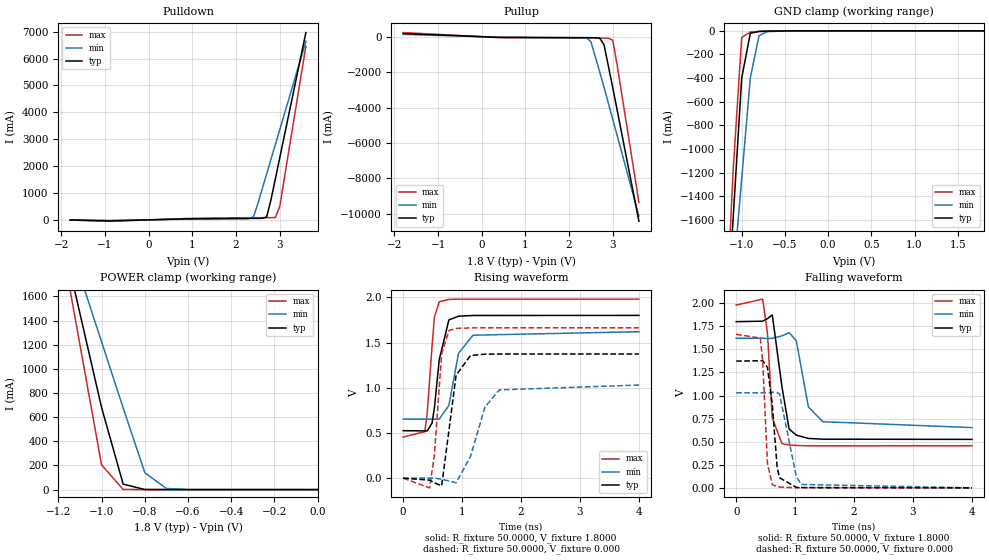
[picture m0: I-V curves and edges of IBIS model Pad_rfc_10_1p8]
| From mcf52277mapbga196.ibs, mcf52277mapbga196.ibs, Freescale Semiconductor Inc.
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|   Model Pad_rfc_10_1p8
[Model]   Pad_rfc_10_1p8
Model_type   3-state
Polarity   Non-Inverting
Enable   Active-High
Vmeas =   0.9000V
C_comp   1.7450pF   1.6200pF   1.8900pF
[Temperature Range]   25.0000   0.1500k   -40.0000
[Voltage Range]   1.8000V   1.6200V   1.9800V
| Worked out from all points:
|   slope of the pulldown table from 0 to 0.27 V, typ, clamps not added: 19 ohm
|   slope of the pullup table from 0 to 0.27 V, typ, clamps not added: 13.8 ohm
|   GND clamp passes 1 mA (typ) near -0.62 V on its own axis
|   POWER clamp passes 1 mA (typ) near -0.80 V on its own axis
|   rising waveform, R_fixture 50.0000, V_fixture 1.8000: 20-80 % time 147ps typ, 186ps min, 105ps max; typ from 0.525 V to 1.8 V
|   rising waveform, R_fixture 50.0000, V_fixture 0.000: 20-80 % time 158ps typ, 298ps min, 109ps max; typ from 0 V to 1.37 V
|   falling waveform, R_fixture 50.0000, V_fixture 1.8000: 20-80 % time 127ps typ, 192ps min, 81.5ps max; typ from 1.8 V to 0.525 V
|   falling waveform, R_fixture 50.0000, V_fixture 0.000: 20-80 % time 108ps typ, 167ps min, 72.6ps max; typ from 1.37 V to 0 V
[Pulldown]
| voltage   I(typ)   I(min)   I(max)
-1.8V     -4.24mA    -2.09mA    -7.86mA
-900mV    -41mA      -20.4mA    -54.37mA
900mV     38.52mA    24.29mA    52.61mA
2.3V      56.35mA    39.44mA    79.95mA
2.4V      56.6mA     115.4mA    80.28mA
2.5V      56.84mA    601.5mA    80.58mA
2.6V      57.95mA    1.15A      80.85mA
2.7V      102.6mA    1.699A     81.1mA
2.8V      738.4mA    2.247A     81.35mA
2.9V      1.517A     2.796A     85.38mA
3V        2.296A     3.345A     485.9mA
3.6V      6.968A     6.645A     6.46A
[Pullup]
| voltage   I(typ)   I(min)   I(max)
-1.8V     193.5mA    144.4mA    246.3mA
400mV     -26.32mA   -16.73mA   -39.42mA
2.4V      -41.73mA   -53.46mA   -62.76mA
2.5V      -43.5mA    -274.4mA   -63.07mA
2.7V      -61.67mA   -1.963A    -66.64mA
2.8V      -440.4mA   -2.842A    -70.12mA
2.9V      -1.643A    -3.748A    -75.32mA
3V        -2.874A    -4.656A    -184.4mA
3.1V      -4.121A    -5.562A    -1.567A
3.6V      -10.43A    -10.13A    -9.366A
[GND_clamp]
| voltage   I(typ)   I(min)   I(max)
-1.8V     -10.39A    -8.454A    -12.14A
-1.2V     -2.833A    -2.997A    -2.746A
-1.1V     -1.601A    -2.108A    -1.195A
-1V       -399mA     -1.252A    -56.61mA
-900mV    -20.31mA   -398.2mA   -10.19mA
-800mV    -5.193mA   -41.09mA   -5.939mA
-700mV    -2.389mA   -6.145mA   -2.797mA
-400mV    -10.19uA   -60.07uA   -3.537uA
1.8V      460.9pA    80.51nA    11.42pA
[POWER_clamp]
| voltage   I(typ)   I(min)   I(max)
-1.8V     6.91A      5.617A     8.169A
-1.2V     2.238A     2.322A     2.196A
-1.1V     1.459A     1.774A     1.2A
-1V       681mA      1.225A     205.3mA
-900mV    45.38mA    676.7mA    1.42mA
-800mV    926.3uA    140.3mA    9.915uA
-700mV    19.1uA     9.035mA    78.66nA
-600mV    427.3nA    583uA      682.7pA
0V        460.9pA    46.95nA    15.9pA
[Ramp]
| variable   typ   min   max
dV/dt_r   0.8238/0.1616n   0.6183/0.2900n   0.9975/98.5664p
dV/dt_f   0.7650/0.1129n   0.5803/0.1979n   0.9147/76.7022p
R_load = 50.0000
[Rising Waveform]
R_fixture = 50.0000
V_fixture = 1.8000
V_fixture_min = 1.6200
V_fixture_max = 1.9800
| time   V(typ)   V(min)   V(max)
0s        525mV      652.8mV    455.5mV
367.3ps   522.7mV    652.8mV    513.4mV
408.2ps   522.5mV    653mV      719.4mV
489.8ps   607.7mV    653.4mV    1.456V
530.6ps   779.9mV    653mV      1.785V
612.2ps   1.309V     652.7mV    1.95V
775.5ps   1.75V      803.8mV    1.977V
938.8ps   1.791V     1.38V      1.98V
1.184ns   1.799V     1.581V     1.98V
4ns       1.8V       1.62V      1.98V
[Rising Waveform]
R_fixture = 50.0000
V_fixture = 0.000
| time   V(typ)   V(min)   V(max)
0s        116.1pV    1.167nV    52.38pV
449ps     -21.92mV   421.9uV    -107.2mV
530.6ps   -51.1mV    528.4uV    263.8mV
653.1ps   -85.23mV   -12.41mV   1.373V
775.5ps   521.6mV    -30.32mV   1.633V
898ps     1.139V     -51.12mV   1.656V
1.143ns   1.357V     240.8mV    1.662V
1.388ns   1.371V     787.9mV    1.663V
1.633ns   1.373V     976.3mV    1.663V
4ns       1.373V     1.03V      1.663V
[Falling Waveform]
R_fixture = 50.0000
V_fixture = 1.8000
V_fixture_min = 1.6200
V_fixture_max = 1.9800
| time   V(typ)   V(min)   V(max)
0s        1.8V       1.62V      1.98V
449ps     1.805V     1.62V      2.044V
530.6ps   1.833V     1.619V     1.675V
612.2ps   1.873V     1.619V     759.3mV
775.5ps   1.098V     1.646V     479.7mV
898ps     636.2mV    1.681V     464.6mV
1.02ns    570.9mV    1.593V     458.9mV
1.225ns   535.3mV    876.7mV    456mV
1.469ns   527.1mV    716.5mV    455.5mV
4ns       525mV      652.8mV    455.5mV
[Falling Waveform]
R_fixture = 50.0000
V_fixture = 0.000
| time   V(typ)   V(min)   V(max)
0s        1.373V     1.03V      1.663V
408.2ps   1.376V     1.03V      1.622V
449ps     1.379V     1.03V      1.384V
530.6ps   1.304V     1.03V      263.7mV
612.2ps   906.2mV    1.036V     34.72mV
693.9ps   226.8mV    1.033V     12.15mV
734.7ps   109.2mV    1.018V     8.889mV
1.02ns    5.739mV    123mV      1.009mV
1.102ns   3.514mV    36.96mV    462.4uV
4ns       1.014uV    1.269uV    988.2nV
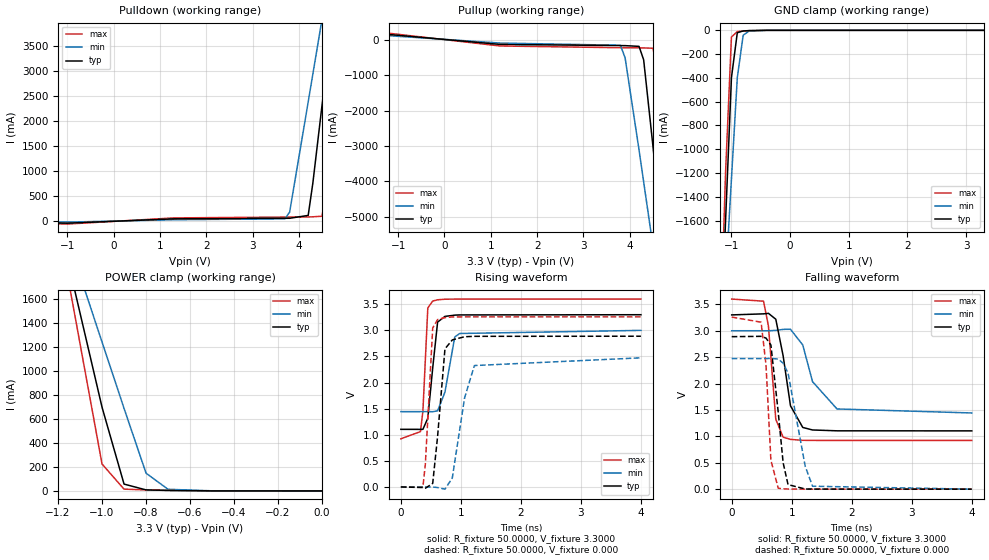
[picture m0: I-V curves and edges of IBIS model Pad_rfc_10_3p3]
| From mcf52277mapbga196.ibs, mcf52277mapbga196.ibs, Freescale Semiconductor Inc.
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|   Model Pad_rfc_10_3p3
[Model]   Pad_rfc_10_3p3
Model_type   3-state
Polarity   Non-Inverting
Enable   Active-High
Vmeas =   1.6500V
C_comp   1.7450pF   1.6200pF   1.8900pF
[Temperature Range]   25.0000   0.1500k   -40.0000
[Voltage Range]   3.3000V   3.0000V   3.6000V
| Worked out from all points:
|   slope of the pulldown table from 0 to 0.495 V, typ, clamps not added: 20.4 ohm
|   slope of the pullup table from 0 to 0.495 V, typ, clamps not added: 7.35 ohm
|   GND clamp passes 1 mA (typ) near -0.62 V on its own axis
|   POWER clamp passes 1 mA (typ) near -0.55 V on its own axis
|   rising waveform, R_fixture 50.0000, V_fixture 3.3000: 20-80 % time 109ps typ, 138ps min, 64.4ps max; typ from 1.1 V to 3.3 V
|   rising waveform, R_fixture 50.0000, V_fixture 0.000: 20-80 % time 108ps typ, 218ps min, 88ps max; typ from 0 V to 2.89 V
|   falling waveform, R_fixture 50.0000, V_fixture 3.3000: 20-80 % time 167ps typ, 305ps min, 108ps max; typ from 3.3 V to 1.1 V
|   falling waveform, R_fixture 50.0000, V_fixture 0.000: 20-80 % time 140ps typ, 218ps min, 94.3ps max; typ from 2.89 V to 0 V
[Pulldown]
| voltage   I(typ)   I(min)   I(max)
-3.3V     -580uA     -420uA     -670uA
-1V       -38.65mA   -17.24mA   -56.16mA
1.3V      48.08mA    29.83mA    66.61mA
3.7V      58.74mA    49.36mA    83.01mA
3.8V      59.21mA    183.6mA    83.2mA
4.2V      116.4mA    2.382A     85.76mA
4.3V      756.8mA    2.935A     88.93mA
4.5V      2.325A     4.043A     99.78mA
4.7V      3.895A     5.151A     1.311A
4.9V      5.466A     6.261A     3.317A
5.1V      7.038A     7.371A     5.325A
6.6V      18.85A     15.72A     20.42A
[Pullup]
| voltage   I(typ)   I(min)   I(max)
-3.3V     244.9mA    215.1mA    284.9mA
-1.5V     192.1mA    148mA      237.4mA
1.2V      -124.2mA   -85.59mA   -168.9mA
3.8V      -157.7mA   -149mA     -218.2mA
3.9V      -158.8mA   -506.4mA   -218.8mA
4.2V      -179.6mA   -3.106A    -221.2mA
4.3V      -558.8mA   -4.013A    -223.9mA
4.5V      -2.994A    -5.827A    -232.9mA
4.7V      -5.497A    -7.651A    -1.42A
4.9V      -8.023A    -9.485A    -4.532A
5.1V      -10.56A    -11.33A    -7.657A
6.6V      -29.85A    -25.37A    -31.75A
[GND_clamp]
| voltage   I(typ)   I(min)   I(max)
-3.3V     -29.47A    -22.32A    -36.02A
-1.2V     -2.833A    -2.997A    -2.746A
-1.1V     -1.601A    -2.108A    -1.195A
-1V       -399mA     -1.252A    -56.61mA
-900mV    -20.31mA   -398.2mA   -10.19mA
-800mV    -5.193mA   -41.09mA   -5.939mA
-700mV    -2.389mA   -6.145mA   -2.797mA
-400mV    -10.19uA   -60.09uA   -3.537uA
3.3V      1.753nA    18.97uA    123.1pA
[POWER_clamp]
| voltage   I(typ)   I(min)   I(max)
-3.3V     18.78A     14A        23.32A
-1.2V     2.265A     2.345A     2.228A
-1.1V     1.481A     1.792A     1.226A
-1V       697mA      1.24A      224.1mA
-900mV    56.88mA    687.4mA    14.75mA
-800mV    8.425mA    147.7mA    8.532mA
-700mV    4.193mA    13.57mA    4.564mA
-500mV    349.8uA    802.1uA    248.4uA
0V        1.753nA    96.55nA    128.5pA
[Ramp]
| variable   typ   min   max
dV/dt_r   1.7329/0.1090n   1.4845/0.1940n   1.9554/72.8575p
dV/dt_f   1.3177/0.1566n   0.9340/0.2906n   1.6064/0.1018n
R_load = 50.0000
[Rising Waveform]
R_fixture = 50.0000
V_fixture = 3.3000
V_fixture_min = 3.0000
V_fixture_max = 3.6000
| time   V(typ)   V(min)   V(max)
0s        1.104V     1.443V     922.7mV
326.5ps   1.103V     1.443V     1.06V
367.3ps   1.104V     1.444V     1.451V
449ps     1.317V     1.444V     3.43V
530.6ps   2.278V     1.442V     3.562V
612.2ps   3.159V     1.458V     3.586V
734.7ps   3.268V     1.817V     3.597V
898ps     3.292V     2.873V     3.599V
979.6ps   3.296V     2.94V      3.6V
4ns       3.3V       3V         3.6V
[Rising Waveform]
R_fixture = 50.0000
V_fixture = 0.000
| time   V(typ)   V(min)   V(max)
0s        904.2pV    217.8nV    -259.9pV
367.3ps   -11.01mV   100.4uV    414.8uV
408.2ps   -24.07mV   387uV      437.3mV
530.6ps   68.21mV    -1.267mV   3.046V
612.2ps   970.1mV    -11.67mV   3.207V
734.7ps   2.646V     -42.51mV   3.245V
857.1ps   2.817V     172.3mV    3.257V
1.061ns   2.878V     1.703V     3.259V
1.225ns   2.886V     2.326V     3.259V
4ns       2.888V     2.474V     3.259V
[Falling Waveform]
R_fixture = 50.0000
V_fixture = 3.3000
V_fixture_min = 3.0000
V_fixture_max = 3.6000
| time   V(typ)   V(min)   V(max)
0s        3.3V       3V         3.6V
530.6ps   3.32V      3V         3.56V
612.2ps   3.33V      2.999V     3.088V
734.7ps   3.218V     3.007V     1.324V
857.1ps   2.525V     3.026V     984.7mV
979.6ps   1.579V     3.028V     942.8mV
1.184ns   1.169V     2.731V     925.3mV
1.347ns   1.121V     2.036V     923.1mV
1.755ns   1.105V     1.519V     922.7mV
4ns       1.104V     1.443V     922.7mV
[Falling Waveform]
R_fixture = 50.0000
V_fixture = 0.000
| time   V(typ)   V(min)   V(max)
0s        2.888V     2.474V     3.259V
489.8ps   2.894V     2.474V     3.162V
571.4ps   2.861V     2.474V     2.358V
653.1ps   2.731V     2.476V     549.1mV
775.5ps   1.455V     2.464V     17.38mV
857.1ps   499.2mV    2.385V     7.46mV
938.8ps   86.23mV    2.202V     2.921mV
1.225ns   3.181mV    433.2mV    249.9uV
1.347ns   1.478mV    55.59mV    -13.47uV
4ns       2.13uV     21.11uV    1.913uV
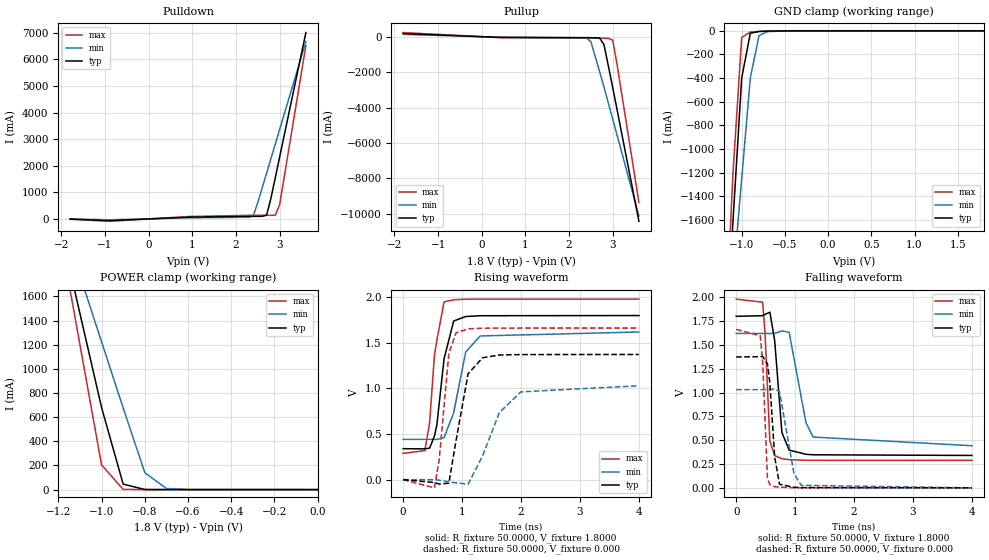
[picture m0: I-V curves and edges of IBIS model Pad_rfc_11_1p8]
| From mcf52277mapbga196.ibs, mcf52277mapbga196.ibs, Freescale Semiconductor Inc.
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|   Model Pad_rfc_11_1p8
[Model]   Pad_rfc_11_1p8
Model_type   3-state
Polarity   Non-Inverting
Enable   Active-High
Vmeas =   0.9000V
C_comp   1.7450pF   1.6200pF   1.8900pF
[Temperature Range]   25.0000   0.1500k   -40.0000
[Voltage Range]   1.8000V   1.6200V   1.9800V
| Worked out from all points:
|   slope of the pulldown table from 0 to 0.27 V, typ, clamps not added: 11.4 ohm
|   slope of the pullup table from 0 to 0.27 V, typ, clamps not added: 13.8 ohm
|   GND clamp passes 1 mA (typ) near -0.62 V on its own axis
|   POWER clamp passes 1 mA (typ) near -0.80 V on its own axis
|   rising waveform, R_fixture 50.0000, V_fixture 1.8000: 20-80 % time 153ps typ, 217ps min, 141ps max; typ from 0.34 V to 1.8 V
|   rising waveform, R_fixture 50.0000, V_fixture 0.000: 20-80 % time 222ps typ, 420ps min, 140ps max; typ from 0 V to 1.37 V
|   falling waveform, R_fixture 50.0000, V_fixture 1.8000: 20-80 % time 109ps typ, 192ps min, 72.2ps max; typ from 1.8 V to 0.34 V
|   falling waveform, R_fixture 50.0000, V_fixture 0.000: 20-80 % time 91.2ps typ, 134ps min, 63.6ps max; typ from 1.37 V to 0 V
[Pulldown]
| voltage   I(typ)   I(min)   I(max)
-1.8V     -7.07mA    -3.484mA   -13.1mA
-900mV    -68.33mA   -34mA      -90.62mA
900mV     64.2mA     40.48mA    87.68mA
2.3V      93.91mA    62.26mA    133.2mA
2.4V      94.32mA    138.3mA    133.8mA
2.5V      94.72mA    624.5mA    134.3mA
2.6V      95.97mA    1.173A     134.7mA
2.7V      140.7mA    1.722A     135.2mA
2.8V      776.6mA    2.271A     135.6mA
2.9V      1.555A     2.819A     139.7mA
3V        2.334A     3.368A     540.4mA
3.6V      7.008A     6.669A     6.515A
[Pullup]
| voltage   I(typ)   I(min)   I(max)
-1.8V     193.5mA    144.4mA    246.3mA
400mV     -26.32mA   -16.73mA   -39.42mA
2.4V      -41.73mA   -53.46mA   -62.76mA
2.5V      -43.5mA    -274.4mA   -63.07mA
2.7V      -61.67mA   -1.963A    -66.64mA
2.8V      -440.4mA   -2.842A    -70.12mA
2.9V      -1.643A    -3.748A    -75.32mA
3V        -2.874A    -4.656A    -184.4mA
3.1V      -4.121A    -5.562A    -1.567A
3.6V      -10.43A    -10.13A    -9.366A
[GND_clamp]
| voltage   I(typ)   I(min)   I(max)
-1.8V     -10.39A    -8.454A    -12.14A
-1.2V     -2.833A    -2.997A    -2.746A
-1.1V     -1.601A    -2.108A    -1.195A
-1V       -399mA     -1.252A    -56.61mA
-900mV    -20.31mA   -398.2mA   -10.19mA
-800mV    -5.193mA   -41.09mA   -5.939mA
-700mV    -2.389mA   -6.145mA   -2.797mA
-400mV    -10.19uA   -60.07uA   -3.537uA
1.8V      460.9pA    80.51nA    11.42pA
[POWER_clamp]
| voltage   I(typ)   I(min)   I(max)
-1.8V     6.91A      5.617A     8.169A
-1.2V     2.238A     2.322A     2.196A
-1.1V     1.459A     1.774A     1.2A
-1V       681mA      1.225A     205.3mA
-900mV    45.38mA    676.7mA    1.42mA
-800mV    926.3uA    140.3mA    9.915uA
-700mV    19.1uA     9.035mA    78.66nA
-600mV    427.3nA    583uA      682.7pA
0V        460.9pA    46.95nA    15.9pA
[Ramp]
| variable   typ   min   max
dV/dt_r   0.8238/0.2250n   0.6182/0.4129n   0.9975/0.1353n
dV/dt_f   0.8760/0.1014n   0.7067/0.1733n   1.0147/67.7223p
R_load = 50.0000
[Rising Waveform]
R_fixture = 50.0000
V_fixture = 1.8000
V_fixture_min = 1.6200
V_fixture_max = 1.9800
| time   V(typ)   V(min)   V(max)
0s        340mV      442.1mV    288.8mV
367.3ps   337.8mV    442mV      318.5mV
449ps     346mV      442.4mV    623.5mV
530.6ps   478.4mV    441.8mV    1.365V
571.4ps   597.8mV    440.7mV    1.527V
693.9ps   1.325V     461.6mV    1.95V
857.1ps   1.74V      733.9mV    1.973V
1.061ns   1.789V     1.4V       1.979V
1.306ns   1.798V     1.576V     1.98V
4ns       1.8V       1.62V      1.98V
[Rising Waveform]
R_fixture = 50.0000
V_fixture = 0.000
| time   V(typ)   V(min)   V(max)
0s        101.9pV    866.4pV    39.03pV
530.6ps   -31.02mV   11.78uV    -89.75mV
612.2ps   -48.16mV   -6.161mV   223.6mV
775.5ps   -38.3mV    -23.68mV   1.385V
898ps     432.7mV    -35mV      1.61V
1.102ns   1.161V     -48.44mV   1.655V
1.347ns   1.337V     259.9mV    1.661V
1.633ns   1.367V     736.7mV    1.662V
2ns       1.372V     963.3mV    1.663V
4ns       1.373V     1.03V      1.663V
[Falling Waveform]
R_fixture = 50.0000
V_fixture = 1.8000
V_fixture_min = 1.6200
V_fixture_max = 1.9800
| time   V(typ)   V(min)   V(max)
0s        1.8V       1.62V      1.98V
449ps     1.806V     1.62V      1.948V
489.8ps   1.82V      1.62V      1.618V
571.4ps   1.843V     1.619V     487.5mV
653.1ps   1.544V     1.622V     338.9mV
775.5ps   580.8mV    1.646V     305.8mV
898ps     396.4mV    1.632V     295.6mV
1.184ns   352.1mV    683.7mV    289.9mV
1.306ns   347mV      533mV      289.4mV
4ns       340mV      442.1mV    288.8mV
[Falling Waveform]
R_fixture = 50.0000
V_fixture = 0.000
| time   V(typ)   V(min)   V(max)
0s        1.373V     1.03V      1.663V
408.2ps   1.376V     1.03V      1.596V
449ps     1.379V     1.03V      1.32V
530.6ps   1.3V       1.03V      96.22mV
571.4ps   1.098V     1.032V     34.02mV
653.1ps   323.2mV    1.037V     11.72mV
734.7ps   37.98mV    1.01V      7.246mV
979.6ps   5.474mV    153.1mV    1.201mV
1.102ns   3.112mV    26.38mV    454.8uV
4ns       720.1nV    6.351uV    646.4nV
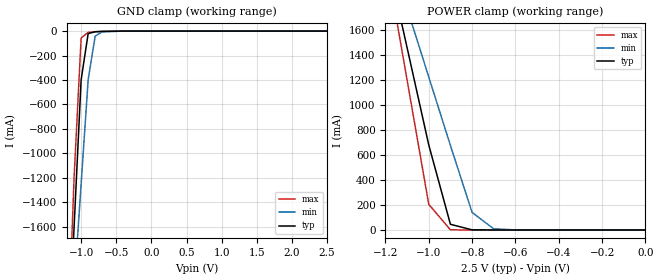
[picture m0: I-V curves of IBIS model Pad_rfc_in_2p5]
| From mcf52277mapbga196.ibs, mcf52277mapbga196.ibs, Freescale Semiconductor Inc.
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|   Model Pad_rfc_in_2p5
[Model]   Pad_rfc_in_2p5
Model_type   Input
Polarity   Non-Inverting
Vinl =   0.7500V
Vinh =   1.7500V
C_comp   1.7450pF   1.6200pF   1.8900pF
[Temperature Range]   25.0000   0.1500k   -40.0000
[Voltage Range]   2.5000V   2.2500V   2.7500V
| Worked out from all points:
|   GND clamp passes 1 mA (typ) near -0.62 V on its own axis
|   POWER clamp passes 1 mA (typ) near -0.80 V on its own axis
[GND_clamp]
| voltage   I(typ)   I(min)   I(max)
-2.5V     -19.27A    -14.9A     -23.25A
-1.2V     -2.833A    -2.997A    -2.746A
-1.1V     -1.601A    -2.108A    -1.195A
-1V       -399mA     -1.252A    -56.61mA
-900mV    -20.31mA   -398.2mA   -10.19mA
-800mV    -5.193mA   -41.09mA   -5.939mA
-700mV    -2.389mA   -6.145mA   -2.797mA
-400mV    -10.19uA   -60.07uA   -3.537uA
2.5V      1.128nA    208.6nA    39.38pA
[POWER_clamp]
| voltage   I(typ)   I(min)   I(max)
-2.5V     12.42A     9.511A     15.21A
-1.2V     2.239A     2.325A     2.196A
-1.1V     1.46A      1.775A     1.201A
-1V       681mA      1.225A     205.3mA
-900mV    45.39mA    676.7mA    1.42mA
-800mV    926.4uA    140.3mA    9.917uA
-700mV    19.11uA    9.036mA    78.78nA
-600mV    428.3nA    583.1uA    762.2pA
0V        1.128nA    78.55nA    61.1pA
